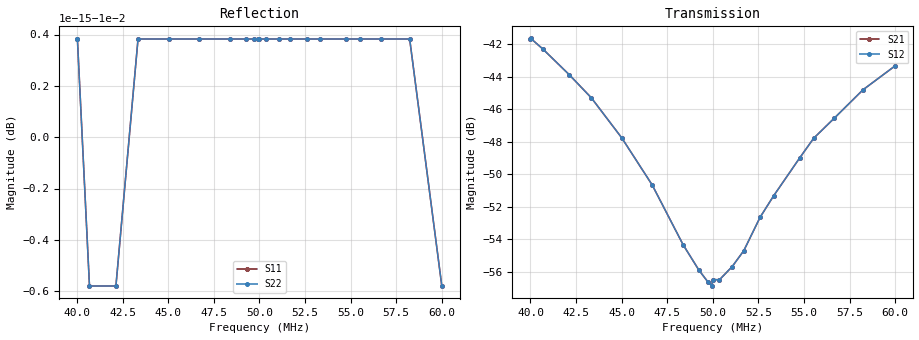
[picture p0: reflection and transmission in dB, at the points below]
!s-Parameter Generated by FASTRON Sdn. Bhd.
!FASTRON P/N : MECC-180X
!Keysight Technologies,E4991B,MY54100416,A.01.15
!Date: Fri Aug 21 09:00:11 2026
!Version  : Rev00 Fri Aug 21 09:00:11 2026
!Data & Calibration Information:
!PortZ  Port1:50+j0  Port2:50+j0
!When reading, reference impedance value at option line is always used.
!Remarks : This data is being provided solely for informational purposes.
!Freq	S11	S21	S12	S22
# Hz S dB R 50
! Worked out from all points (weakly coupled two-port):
!   1601 points, 40 MHz to 60 MHz, reference 50 ohm
!   highest |S21| = -41.65 dB at 40.01 MHz (marker M1); lowest = -56.8 dB at 49.94 MHz (marker M2)
!   lowest |S11| = 0.0 dB at 40.67 MHz (marker M3)
!   |S11| at or under -10 dB: nowhere
!   |S22| runs from 0.0 to 0.0 dB; largest |S21 - S12| = 0
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4e7  -0.01 0.5  -41.66 -78.4  -41.66 -78.4  -0.01 0.5
4.00125e7  -0.01 0.5  -41.65 -78.4  -41.65 -78.4  -0.01 0.5
4.0675e7  -0.01 0.4  -42.30 -77.3  -42.30 -77.3  -0.01 0.4
4.2125e7  -0.01 0.4  -43.88 -75.6  -43.88 -75.6  -0.01 0.4
4.33375e7  -0.01 0.3  -45.30 -73.5  -45.30 -73.5  -0.01 0.3
4.50125e7  -0.01 0.2  -47.77 -68.1  -47.77 -68.1  -0.01 0.2
4.6675e7  -0.01 0.1  -50.65 -59.1  -50.65 -59.1  -0.01 0.1
4.8375e7  -0.01 0.1  -54.33 -38.3  -54.33 -38.3  -0.01 0.1
4.92375e7  -0.01 0.0  -55.88 -20.6  -55.88 -20.6  -0.01 0.0
4.9725e7  -0.01 0.0  -56.60 -9.4  -56.60 -9.4  -0.01 0.0
4.99375e7  -0.01 0.0  -56.84 -2.5  -56.84 -2.5  -0.01 0.0
5e7  -0.01 0.0  -56.46 -0.5  -56.46 -0.5  -0.01 0.0
5.03625e7  -0.01 -0.0  -56.48 8.9  -56.48 8.9  -0.01 -0.0
5.10625e7  -0.01 -0.0  -55.67 27.4  -55.67 27.4  -0.01 -0.0
5.17e7  -0.01 -0.1  -54.69 39.1  -54.69 39.1  -0.01 -0.1
5.26e7  -0.01 -0.1  -52.63 51.7  -52.63 51.7  -0.01 -0.1
5.33375e7  -0.01 -0.1  -51.32 58.5  -51.32 58.5  -0.01 -0.1
5.47625e7  -0.01 -0.2  -49.00 65.7  -49.00 65.7  -0.01 -0.2
5.55375e7  -0.01 -0.2  -47.78 69.1  -47.78 69.1  -0.01 -0.2
5.6675e7  -0.01 -0.3  -46.54 72.4  -46.54 72.4  -0.01 -0.3
5.82375e7  -0.01 -0.3  -44.81 75.6  -44.81 75.6  -0.01 -0.3
6e7  -0.01 -0.4  -43.34 77.9  -43.34 77.9  -0.01 -0.4
